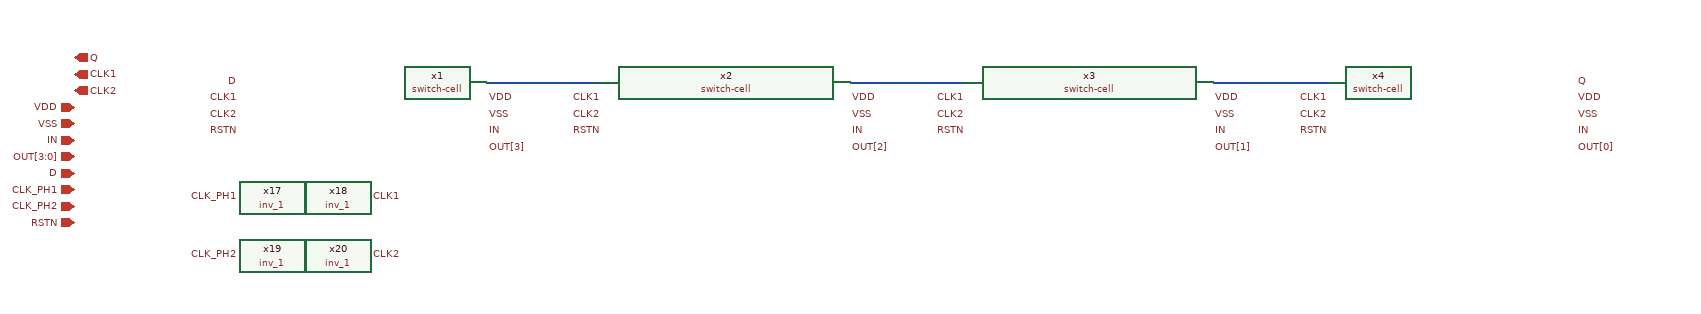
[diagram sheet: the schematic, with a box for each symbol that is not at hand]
v {xschem version=3.4.7 file_version=1.2}
G {}
K {}
V {}
S {}
E {}
N 600 -250 740 -250 {lab=#net1}
N 1040 -250 1180 -250 {lab=#net2}
N 1480 -250 1620 -250 {lab=#net3}
C {lab_wire.sym} 600 -230 0 1 {name=p1 lab=VDD}
C {lab_wire.sym} 600 -210 0 1 {name=p2 lab=VSS}
C {lab_wire.sym} 600 -190 0 1 {name=p5 lab=IN}
C {lab_wire.sym} 600 -170 0 1 {name=p6 lab=OUT[3]}
C {iopin.sym} 100 -180 0 0 {name=p8 lab=IN}
C {iopin.sym} 100 -160 0 0 {name=p9 lab=OUT[3:0]}
C {lab_wire.sym} 300 -250 0 0 {name=p12 lab=D}
C {lab_wire.sym} 1040 -230 0 1 {name=p15 lab=VDD}
C {lab_wire.sym} 1040 -210 0 1 {name=p16 lab=VSS}
C {lab_wire.sym} 1040 -190 0 1 {name=p18 lab=IN}
C {lab_wire.sym} 1040 -170 0 1 {name=p19 lab=OUT[2]}
C {lab_wire.sym} 1480 -230 0 1 {name=p22 lab=VDD}
C {lab_wire.sym} 1480 -210 0 1 {name=p23 lab=VSS}
C {lab_wire.sym} 1480 -190 0 1 {name=p25 lab=IN}
C {lab_wire.sym} 1480 -170 0 1 {name=p26 lab=OUT[1]}
C {lab_wire.sym} 1920 -230 0 1 {name=p29 lab=VDD}
C {lab_wire.sym} 1920 -210 0 1 {name=p30 lab=VSS}
C {lab_wire.sym} 1920 -190 0 1 {name=p32 lab=IN}
C {lab_wire.sym} 1920 -170 0 1 {name=p33 lab=OUT[0]}
C {lab_wire.sym} 300 -230 0 0 {name=p4 lab=CLK1}
C {lab_wire.sym} 300 -210 0 0 {name=p11 lab=CLK2}
C {lab_wire.sym} 300 -190 0 0 {name=p17 lab=RSTN}
C {lab_wire.sym} 740 -230 0 0 {name=p21 lab=CLK1}
C {lab_wire.sym} 740 -210 0 0 {name=p24 lab=CLK2}
C {lab_wire.sym} 740 -190 0 0 {name=p27 lab=RSTN}
C {lab_wire.sym} 1180 -230 0 0 {name=p31 lab=CLK1}
C {lab_wire.sym} 1180 -210 0 0 {name=p34 lab=CLK2}
C {lab_wire.sym} 1180 -190 0 0 {name=p35 lab=RSTN}
C {lab_wire.sym} 1620 -230 0 0 {name=p43 lab=CLK1}
C {lab_wire.sym} 1620 -210 0 0 {name=p44 lab=CLK2}
C {lab_wire.sym} 1620 -190 0 0 {name=p45 lab=RSTN}
C {iopin.sym} 100 -220 0 0 {name=p3 lab=VDD}
C {iopin.sym} 100 -200 0 0 {name=p7 lab=VSS}
C {opin.sym} 100 -280 0 0 {name=p144 lab=Q}
C {opin.sym} 100 -260 0 0 {name=p145 lab=CLK1}
C {opin.sym} 100 -240 0 0 {name=p146 lab=CLK2}
C {ipin.sym} 100 -140 0 0 {name=p10 lab=D}
C {ipin.sym} 100 -80 0 0 {name=p13 lab=RSTN}
C {ipin.sym} 100 -120 0 0 {name=p14 lab=CLK_PH1}
C {ipin.sym} 100 -100 0 0 {name=p49 lab=CLK_PH2}
C {lab_wire.sym} 300 -110 0 0 {name=p38 lab=CLK_PH1}
C {lab_wire.sym} 300 -40 0 0 {name=p40 lab=CLK_PH2}
C {lab_wire.sym} 460 -110 0 1 {name=p41 lab=CLK1}
C {lab_wire.sym} 460 -40 0 1 {name=p42 lab=CLK2}
C {libs/gf180mcu_fd_sc_mcu9t5v0_symbols/inv_1.sym} 340 -110 0 0 {name=x17 VGND=VSSd VNB=VDDd VPB=VSSd VPWR=VDDd prefix=gf180mcu_fd_sc_mcu9t5v0__ }
C {libs/gf180mcu_fd_sc_mcu9t5v0_symbols/inv_1.sym} 420 -110 0 0 {name=x18 VGND=VSSd VNB=VDDd VPB=VSSd VPWR=VDDd prefix=gf180mcu_fd_sc_mcu9t5v0__ }
C {libs/gf180mcu_fd_sc_mcu9t5v0_symbols/inv_1.sym} 340 -40 0 0 {name=x19 VGND=VSSd VNB=VDDd VPB=VSSd VPWR=VDDd prefix=gf180mcu_fd_sc_mcu9t5v0__ }
C {libs/gf180mcu_fd_sc_mcu9t5v0_symbols/inv_1.sym} 420 -40 0 0 {name=x20 VGND=VSSd VNB=VDDd VPB=VSSd VPWR=VDDd prefix=gf180mcu_fd_sc_mcu9t5v0__ }
C {lab_wire.sym} 1920 -250 0 1 {name=p20 lab=Q}
C {libs/core_switch-matrix/switch-cell/switch-cell.sym} 450 -210 0 0 {name=x1}
C {libs/core_switch-matrix/switch-cell/switch-cell.sym} 890 -210 0 0 {name=x2}
C {libs/core_switch-matrix/switch-cell/switch-cell.sym} 1330 -210 0 0 {name=x3}
C {libs/core_switch-matrix/switch-cell/switch-cell.sym} 1770 -210 0 0 {name=x4}
